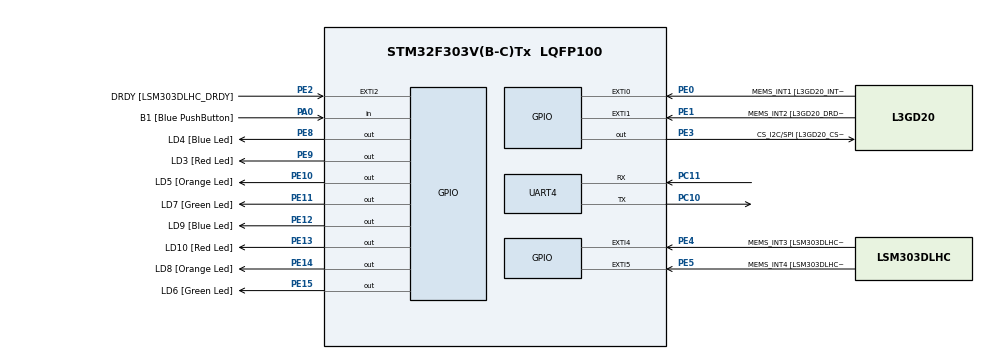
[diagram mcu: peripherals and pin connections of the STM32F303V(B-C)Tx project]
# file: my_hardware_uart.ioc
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Mcu.Family=STM32F3
Mcu.Name=STM32F303V(B-C)Tx
Mcu.Package=LQFP100
NVIC.PriorityGroup=NVIC_PRIORITYGROUP_0
PA0.GPIO_Label=B1 [Blue PushButton]
PA0.GPIO_Mode=GPIO_MODE_INPUT
PA0.GPIO_PuPd=GPIO_NOPULL
PA0.Signal=GPIO_Input
PA11.GPIO_Label=DM
PA11.Signal=USB_DM
PA12.GPIO_Label=DP
PA12.Signal=USB_DP
PA13.GPIO_Label=SWDIO
PA13.Signal=SYS_JTMS-SWDIO
PA14.GPIO_Label=SWCLK
PA14.Signal=SYS_JTCK-SWCLK
PA5.GPIO_Label=SPI1_SCK [L3GD20_SCL/SPC]
PA5.GPIO_Mode=GPIO_MODE_AF_PP
PA5.GPIO_PuPd=GPIO_NOPULL
PA5.GPIO_Speed=GPIO_SPEED_FREQ_LOW
PA5.Signal=SPI1_SCK
PA6.GPIO_Label=SPI1_MISO [L3GD20_SA0/SDO]
PA6.GPIO_Mode=GPIO_MODE_AF_PP
PA6.GPIO_PuPd=GPIO_NOPULL
PA6.GPIO_Speed=GPIO_SPEED_FREQ_LOW
PA6.Signal=SPI1_MISO
PA7.GPIO_Label=SPI1_MISO [L3GD20_SDA/SDI/SDO]
PA7.GPIO_Mode=GPIO_MODE_AF_PP
PA7.GPIO_PuPd=GPIO_NOPULL
PA7.GPIO_Speed=GPIO_SPEED_FREQ_LOW
PA7.Signal=SPI1_MOSI
PB3.GPIO_Label=SWO
PB3.Signal=SYS_JTDO-TRACESWO
PB6.GPIO_FM6=__NULL
PB6.GPIO_Label=I2C1_SCL [LSM303DLHC_SCL]
PB6.GPIO_Mode=GPIO_MODE_AF_OD
PB6.GPIO_PuPd=GPIO_NOPULL
PB6.GPIO_Speed=GPIO_SPEED_FREQ_LOW
PB6.Signal=I2C1_SCL
PB7.GPIO_FM7=__NULL
PB7.GPIO_Label=I2C1_SDA [LSM303DLHC_SDA]
PB7.GPIO_Mode=GPIO_MODE_AF_OD
PB7.GPIO_PuPd=GPIO_NOPULL
PB7.GPIO_Speed=GPIO_SPEED_FREQ_LOW
PB7.Signal=I2C1_SDA
PC10.Mode=Asynchronous
PC10.Signal=UART4_TX
PC11.Mode=Asynchronous
PC11.Signal=UART4_RX
PC14-OSC32_IN.GPIO_Label=OSC32_IN
PC14-OSC32_IN.Signal=RCC_OSC32_IN
PC15-OSC32_OUT.GPIO_Label=OSC32_OUT
PC15-OSC32_OUT.Signal=RCC_OSC32_OUT
PE0.GPIO_Label=MEMS_INT1 [L3GD20_INT1]
PE0.GPIO_ModeDefaultEXTI=GPIO_MODE_EVT_RISING
PE0.GPIO_PuPd=GPIO_NOPULL
PE0.Signal=GPXTI0
PE1.GPIO_Label=MEMS_INT2 [L3GD20_DRDY/INT2]
PE1.GPIO_ModeDefaultEXTI=GPIO_MODE_EVT_RISING
PE1.GPIO_PuPd=GPIO_NOPULL
PE1.Signal=GPXTI1
PE10.GPIO_Label=LD5 [Orange Led]
PE10.GPIO_ModeDefaultOutputPP=GPIO_MODE_OUTPUT_PP
PE10.GPIO_PuPd=GPIO_NOPULL
PE10.GPIO_Speed=GPIO_SPEED_FREQ_LOW
PE10.Signal=GPIO_Output
PE11.GPIO_Label=LD7 [Green Led]
PE11.GPIO_ModeDefaultOutputPP=GPIO_MODE_OUTPUT_PP
PE11.GPIO_PuPd=GPIO_NOPULL
PE11.GPIO_Speed=GPIO_SPEED_FREQ_LOW
PE11.Signal=GPIO_Output
PE12.GPIO_Label=LD9 [Blue Led]
PE12.GPIO_ModeDefaultOutputPP=GPIO_MODE_OUTPUT_PP
PE12.GPIO_PuPd=GPIO_NOPULL
PE12.GPIO_Speed=GPIO_SPEED_FREQ_LOW
PE12.Signal=GPIO_Output
PE13.GPIO_Label=LD10 [Red Led]
PE13.GPIO_ModeDefaultOutputPP=GPIO_MODE_OUTPUT_PP
PE13.GPIO_PuPd=GPIO_NOPULL
PE13.GPIO_Speed=GPIO_SPEED_FREQ_LOW
PE13.Signal=GPIO_Output
PE14.GPIO_Label=LD8 [Orange Led]
PE14.GPIO_ModeDefaultOutputPP=GPIO_MODE_OUTPUT_PP
PE14.GPIO_PuPd=GPIO_NOPULL
PE14.GPIO_Speed=GPIO_SPEED_FREQ_LOW
PE14.Signal=GPIO_Output
PE15.GPIO_Label=LD6 [Green Led]
PE15.GPIO_ModeDefaultOutputPP=GPIO_MODE_OUTPUT_PP
PE15.GPIO_PuPd=GPIO_NOPULL
PE15.GPIO_Speed=GPIO_SPEED_FREQ_LOW
PE15.Signal=GPIO_Output
PE2.GPIO_Label=DRDY [LSM303DLHC_DRDY]
PE2.GPIO_ModeDefaultEXTI=GPIO_MODE_EVT_RISING
PE2.GPIO_PuPd=GPIO_NOPULL
PE2.Signal=GPXTI2
PE3.GPIO_Label=CS_I2C/SPI [L3GD20_CS_I2C/SPI]
PE3.GPIO_ModeDefaultOutputPP=GPIO_MODE_OUTPUT_PP
PE3.GPIO_PuPd=GPIO_NOPULL
PE3.GPIO_Speed=GPIO_SPEED_FREQ_LOW
PE3.Signal=GPIO_Output
PE4.GPIO_Label=MEMS_INT3 [LSM303DLHC_INT1]
PE4.GPIO_ModeDefaultEXTI=GPIO_MODE_EVT_RISING
PE4.GPIO_PuPd=GPIO_NOPULL
PE4.Signal=GPXTI4
PE5.GPIO_Label=MEMS_INT4 [LSM303DLHC_INT2]
PE5.GPIO_ModeDefaultEXTI=GPIO_MODE_EVT_RISING
PE5.GPIO_PuPd=GPIO_NOPULL
PE5.Signal=GPXTI5
PE8.GPIO_Label=LD4 [Blue Led]
PE8.GPIO_ModeDefaultOutputPP=GPIO_MODE_OUTPUT_PP
PE8.GPIO_PuPd=GPIO_NOPULL
PE8.GPIO_Speed=GPIO_SPEED_FREQ_LOW
PE8.Signal=GPIO_Output
PE9.GPIO_Label=LD3 [Red Led]
PE9.GPIO_ModeDefaultOutputPP=GPIO_MODE_OUTPUT_PP
PE9.GPIO_PuPd=GPIO_NOPULL
PE9.GPIO_Speed=GPIO_SPEED_FREQ_LOW
PE9.Signal=GPIO_Output
PF0-OSC_IN.GPIO_Label=OSC_IN
PF0-OSC_IN.Signal=RCC_OSC_IN
PF1-OSC_OUT.GPIO_Label=OSC_OUT
PF1-OSC_OUT.Signal=RCC_OSC_OUT
ProjectManager.HeapSize=0x200
ProjectManager.StackSize=0x400
ProjectManager.TargetToolchain=MDK-ARM V5
RCC.AHBFreq_Value=24000000
RCC.APB1Freq_Value=24000000
RCC.APB1TimFreq_Value=24000000
RCC.APB2Freq_Value=24000000
RCC.APB2TimFreq_Value=24000000
RCC.CortexFreq_Value=24000000
RCC.HCLKFreq_Value=24000000
RCC.HSE_VALUE=8000000
RCC.HSI_VALUE=8000000
RCC.LSE_VALUE=32768
RCC.PLLMUL=RCC_PLL_MUL6
RCC.SYSCLKFreq_VALUE=24000000
RCC.SYSCLKSourceVirtual=RCC_SYSCLKSOURCE_PLLCLK
RCC.USBFreq_Value=24000000
VP_TIM6_VS_ClockSourceINT.Mode=Enable_Timer
VP_TIM7_VS_ClockSourceINT.Mode=Enable_Timer
board=STM32F3DISCOVERY

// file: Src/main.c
/**
  ******************************************************************************
  * @file           : main.c
  * @brief          : Main program body
  ******************************************************************************
  ** This notice applies to any and all portions of this file
  * that are not between comment pairs USER CODE BEGIN and
  * USER CODE END. Other portions of this file, whether
  * inserted by the user or by software development tools
  * are owned by their respective copyright owners.
  *
  * COPYRIGHT(c) 2018 STMicroelectronics
  *
  * Redistribution and use in source and binary forms, with or without modification,
  * are permitted provided that the following conditions are met:
  *   1. Redistributions of source code must retain the above copyright notice,
  *      this list of conditions and the following disclaimer.
  *   2. Redistributions in binary form must reproduce the above copyright notice,
  *      this list of conditions and the following disclaimer in the documentation
  *      and/or other materials provided with the distribution.
  *   3. Neither the name of STMicroelectronics nor the names of its contributors
  *      may be used to endorse or promote products derived from this software
  *      without specific prior written permission.
  *
  * THIS SOFTWARE IS PROVIDED BY THE COPYRIGHT HOLDERS AND CONTRIBUTORS "AS IS"
  * AND ANY EXPRESS OR IMPLIED WARRANTIES, INCLUDING, BUT NOT LIMITED TO, THE
  * IMPLIED WARRANTIES OF MERCHANTABILITY AND FITNESS FOR A PARTICULAR PURPOSE ARE
  * DISCLAIMED. IN NO EVENT SHALL THE COPYRIGHT HOLDER OR CONTRIBUTORS BE LIABLE
  * FOR ANY DIRECT, INDIRECT, INCIDENTAL, SPECIAL, EXEMPLARY, OR CONSEQUENTIAL
  * DAMAGES (INCLUDING, BUT NOT LIMITED TO, PROCUREMENT OF SUBSTITUTE GOODS OR
  * SERVICES; LOSS OF USE, DATA, OR PROFITS; OR BUSINESS INTERRUPTION) HOWEVER
  * CAUSED AND ON ANY THEORY OF LIABILITY, WHETHER IN CONTRACT, STRICT LIABILITY,
  * OR TORT (INCLUDING NEGLIGENCE OR OTHERWISE) ARISING IN ANY WAY OUT OF THE USE
  * OF THIS SOFTWARE, EVEN IF ADVISED OF THE POSSIBILITY OF SUCH DAMAGE.
  *
  ******************************************************************************
  */
#include "main.h"
#include "stm32f3xx_hal.h"
#include "MY_HEADERS.h"
#include <string.h>

TIM_HandleTypeDef htim6;
TIM_HandleTypeDef htim7;

UART_HandleTypeDef huart4;

/* USER CODE BEGIN PV */
/* Private variables ---------------------------------------------------------*/

/* USER CODE END PV */

void SystemClock_Config(void);
static void MX_GPIO_Init(void);
static void MX_UART4_Init(void);
static void MX_TIM6_Init(void);
static void MX_TIM7_Init(void);

/* USER CODE BEGIN PFP */
/* Private function prototypes -----------------------------------------------*/

/* USER CODE END PFP */

/* USER CODE BEGIN 0 */

/* USER CODE BEGIN 4 */
void debugPrint(UART_HandleTypeDef *, char*);

/* USER CODE END 0 */

int main(void)
{

  /* MCU Configuration----------------------------------------------------------*/

  /* Reset of all peripherals, Initializes the Flash interface and the Systick. */
  HAL_Init();

  /* Configure the system clock */
  SystemClock_Config();

  /* Initialize all configured peripherals */
  MX_GPIO_Init();
  MX_TIM6_Init();
  MX_TIM7_Init();
  MX_UART4_Init();
  /* USER CODE BEGIN 2 */
	const uint16_t _size = 1;
	char outbuffer = 0xff;//'H';
	char my_string[_size] = {0};//"I_m_sender_uart4_str_2345678901?"
	uint8_t *my_data;
	uint8_t my_message = 0xFF;
	my_data = &my_message;
	//my_data = (uint8_t*) my_string;
	GPIOE->ODR = 0x00000000;

  /* USER CODE END 2 */

  /* Infinite loop */
  /* USER CODE BEGIN WHILE */
  while (1)
  {
					//debugPrint(&huart4, my_string);
for (;;)
{

	//__HAL_UART_CLEAR_FLAG(huart4, USART_ICR_ORECF);
	if(HAL_TIMEOUT != HAL_UART_Receive(&huart4, my_data, _size, 1000) )//HAL_MAX_DELAY
	{
		if(__HAL_UART_GET_FLAG(&huart4, USART_ICR_ORECF))
		{
			__HAL_UART_CLEAR_FLAG(&huart4, USART_ICR_ORECF);
			GPIOE->ODR = GPIOE->ODR ^ 0x00000200;// PE 9 (RED)
		}
		//my_message = (uint8_t) 'A';
		HAL_UART_Transmit(&huart4, my_data, _size, 1000);

	}
	else
	{
		if(__HAL_UART_GET_FLAG(&huart4, USART_ICR_ORECF))
		{
			__HAL_UART_CLEAR_FLAG(&huart4, USART_ICR_ORECF);
			GPIOE->ODR = GPIOE->ODR ^ 0x00000100;// PE 8
		}
			GPIOE->ODR = GPIOE->ODR ^ 0x00001000;// PE 12
		//my_message = (uint8_t) 'T';
		HAL_UART_Transmit(&huart4, my_data, _size, 1000);

	}

}

  }
  /* USER CODE END 3 */

}

void SystemClock_Config(void)
{

  RCC_OscInitTypeDef RCC_OscInitStruct;
  RCC_ClkInitTypeDef RCC_ClkInitStruct;
  RCC_PeriphCLKInitTypeDef PeriphClkInit;

    /**Initializes the CPU, AHB and APB busses clocks
    */
  RCC_OscInitStruct.OscillatorType = RCC_OSCILLATORTYPE_HSE;
  RCC_OscInitStruct.HSEState = RCC_HSE_ON;
  RCC_OscInitStruct.HSEPredivValue = RCC_HSE_PREDIV_DIV1;
  RCC_OscInitStruct.HSIState = RCC_HSI_ON;
  RCC_OscInitStruct.PLL.PLLState = RCC_PLL_ON;
  RCC_OscInitStruct.PLL.PLLSource = RCC_PLLSOURCE_HSE;
  RCC_OscInitStruct.PLL.PLLMUL = RCC_PLL_MUL9;
  if (HAL_RCC_OscConfig(&RCC_OscInitStruct) != HAL_OK)
  {
    _Error_Handler(__FILE__, __LINE__);
  }

    /**Initializes the CPU, AHB and APB busses clocks
    */
  RCC_ClkInitStruct.ClockType = RCC_CLOCKTYPE_HCLK|RCC_CLOCKTYPE_SYSCLK
                              |RCC_CLOCKTYPE_PCLK1|RCC_CLOCKTYPE_PCLK2;
  RCC_ClkInitStruct.SYSCLKSource = RCC_SYSCLKSOURCE_PLLCLK;
  RCC_ClkInitStruct.AHBCLKDivider = RCC_SYSCLK_DIV1;
  RCC_ClkInitStruct.APB1CLKDivider = RCC_HCLK_DIV2;
  RCC_ClkInitStruct.APB2CLKDivider = RCC_HCLK_DIV1;

  if (HAL_RCC_ClockConfig(&RCC_ClkInitStruct, FLASH_LATENCY_2) != HAL_OK)
  {
    _Error_Handler(__FILE__, __LINE__);
  }

  PeriphClkInit.PeriphClockSelection = RCC_PERIPHCLK_UART4;
  PeriphClkInit.Uart4ClockSelection = RCC_UART4CLKSOURCE_PCLK1;
  if (HAL_RCCEx_PeriphCLKConfig(&PeriphClkInit) != HAL_OK)
  {
    _Error_Handler(__FILE__, __LINE__);
  }

    /**Configure the Systick interrupt time
    */
  HAL_SYSTICK_Config(HAL_RCC_GetHCLKFreq()/1000);

    /**Configure the Systick
    */
  HAL_SYSTICK_CLKSourceConfig(SYSTICK_CLKSOURCE_HCLK);

  /* SysTick_IRQn interrupt configuration */
  HAL_NVIC_SetPriority(SysTick_IRQn, 0, 0);
}

/* TIM6 init function */
static void MX_TIM6_Init(void)
{

  TIM_MasterConfigTypeDef sMasterConfig;

  htim6.Instance = TIM6;
  htim6.Init.Prescaler = 0;
  htim6.Init.CounterMode = TIM_COUNTERMODE_UP;
  htim6.Init.Period = 0;
  htim6.Init.AutoReloadPreload = TIM_AUTORELOAD_PRELOAD_DISABLE;
  if (HAL_TIM_Base_Init(&htim6) != HAL_OK)
  {
    _Error_Handler(__FILE__, __LINE__);
  }

  if (HAL_TIM_OnePulse_Init(&htim6, TIM_OPMODE_SINGLE) != HAL_OK)
  {
    _Error_Handler(__FILE__, __LINE__);
  }

  sMasterConfig.MasterOutputTrigger = TIM_TRGO_RESET;
  sMasterConfig.MasterSlaveMode = TIM_MASTERSLAVEMODE_DISABLE;
  if (HAL_TIMEx_MasterConfigSynchronization(&htim6, &sMasterConfig) != HAL_OK)
  {
    _Error_Handler(__FILE__, __LINE__);
  }

}

/* TIM7 init function */
static void MX_TIM7_Init(void)
{

  TIM_MasterConfigTypeDef sMasterConfig;

  htim7.Instance = TIM7;
  htim7.Init.Prescaler = 0;
  htim7.Init.CounterMode = TIM_COUNTERMODE_UP;
  htim7.Init.Period = 0;
  htim7.Init.AutoReloadPreload = TIM_AUTORELOAD_PRELOAD_DISABLE;
  if (HAL_TIM_Base_Init(&htim7) != HAL_OK)
  {
    _Error_Handler(__FILE__, __LINE__);
  }

  if (HAL_TIM_OnePulse_Init(&htim7, TIM_OPMODE_SINGLE) != HAL_OK)
  {
    _Error_Handler(__FILE__, __LINE__);
  }

  sMasterConfig.MasterOutputTrigger = TIM_TRGO_RESET;
  sMasterConfig.MasterSlaveMode = TIM_MASTERSLAVEMODE_DISABLE;
  if (HAL_TIMEx_MasterConfigSynchronization(&htim7, &sMasterConfig) != HAL_OK)
  {
    _Error_Handler(__FILE__, __LINE__);
  }

}

/* UART4 init function */
static void MX_UART4_Init(void)
{

  huart4.Instance = UART4;
  huart4.Init.BaudRate = 9600;//115200;
  huart4.Init.WordLength = UART_WORDLENGTH_8B;
  huart4.Init.StopBits = UART_STOPBITS_1;
  huart4.Init.Parity = UART_PARITY_NONE;
  huart4.Init.Mode = UART_MODE_TX_RX;
  huart4.Init.HwFlowCtl = UART_HWCONTROL_NONE;
  huart4.Init.OverSampling = UART_OVERSAMPLING_16;
  huart4.Init.OneBitSampling = UART_ONE_BIT_SAMPLE_DISABLE;
  huart4.AdvancedInit.AdvFeatureInit = UART_ADVFEATURE_NO_INIT;
  if (HAL_UART_Init(&huart4) != HAL_OK)
  {
    _Error_Handler(__FILE__, __LINE__);
  }

}

/** Configure pins as
        * Analog
        * Input
        * Output
        * EVENT_OUT
        * EXTI
     PA5   ------> SPI1_SCK
     PA6   ------> SPI1_MISO
     PA7   ------> SPI1_MOSI
     PA11   ------> USB_DM
     PA12   ------> USB_DP
     PB6   ------> I2C1_SCL
     PB7   ------> I2C1_SDA
*/
static void MX_GPIO_Init(void)
{

  GPIO_InitTypeDef GPIO_InitStruct;

  /* GPIO Ports Clock Enable */
  __HAL_RCC_GPIOE_CLK_ENABLE();
  __HAL_RCC_GPIOC_CLK_ENABLE();
  __HAL_RCC_GPIOF_CLK_ENABLE();
  __HAL_RCC_GPIOA_CLK_ENABLE();
  __HAL_RCC_GPIOB_CLK_ENABLE();

  /*Configure GPIO pin Output Level */
  HAL_GPIO_WritePin(GPIOE, CS_I2C_SPI_Pin|LD4_Pin|LD3_Pin|LD5_Pin
                          |LD7_Pin|LD9_Pin|LD10_Pin|LD8_Pin
                          |LD6_Pin, GPIO_PIN_RESET);

  /*Configure GPIO pins : DRDY_Pin MEMS_INT3_Pin MEMS_INT4_Pin MEMS_INT1_Pin
                           MEMS_INT2_Pin */
  GPIO_InitStruct.Pin = DRDY_Pin|MEMS_INT3_Pin|MEMS_INT4_Pin|MEMS_INT1_Pin
                          |MEMS_INT2_Pin;
  GPIO_InitStruct.Mode = GPIO_MODE_EVT_RISING;
  GPIO_InitStruct.Pull = GPIO_NOPULL;
  HAL_GPIO_Init(GPIOE, &GPIO_InitStruct);

  /*Configure GPIO pins : CS_I2C_SPI_Pin LD4_Pin LD3_Pin LD5_Pin
                           LD7_Pin LD9_Pin LD10_Pin LD8_Pin
                           LD6_Pin */
  GPIO_InitStruct.Pin = CS_I2C_SPI_Pin|LD4_Pin|LD3_Pin|LD5_Pin
                          |LD7_Pin|LD9_Pin|LD10_Pin|LD8_Pin
                          |LD6_Pin;
  GPIO_InitStruct.Mode = GPIO_MODE_OUTPUT_PP;
  GPIO_InitStruct.Pull = GPIO_NOPULL;
  GPIO_InitStruct.Speed = GPIO_SPEED_FREQ_LOW;
  HAL_GPIO_Init(GPIOE, &GPIO_InitStruct);

  /*Configure GPIO pin : B1_Pin */
  GPIO_InitStruct.Pin = B1_Pin;
  GPIO_InitStruct.Mode = GPIO_MODE_INPUT;
  GPIO_InitStruct.Pull = GPIO_NOPULL;
  HAL_GPIO_Init(B1_GPIO_Port, &GPIO_InitStruct);

  /*Configure GPIO pins : SPI1_SCK_Pin SPI1_MISO_Pin SPI1_MISOA7_Pin */
  GPIO_InitStruct.Pin = SPI1_SCK_Pin|SPI1_MISO_Pin|SPI1_MISOA7_Pin;
  GPIO_InitStruct.Mode = GPIO_MODE_AF_PP;
  GPIO_InitStruct.Pull = GPIO_NOPULL;
  GPIO_InitStruct.Speed = GPIO_SPEED_FREQ_LOW;
  GPIO_InitStruct.Alternate = GPIO_AF5_SPI1;
  HAL_GPIO_Init(GPIOA, &GPIO_InitStruct);

  /*Configure GPIO pins : DM_Pin DP_Pin */
  GPIO_InitStruct.Pin = DM_Pin|DP_Pin;
  GPIO_InitStruct.Mode = GPIO_MODE_AF_PP;
  GPIO_InitStruct.Pull = GPIO_NOPULL;
  GPIO_InitStruct.Speed = GPIO_SPEED_FREQ_HIGH;
  GPIO_InitStruct.Alternate = GPIO_AF14_USB;
  HAL_GPIO_Init(GPIOA, &GPIO_InitStruct);

  /*Configure GPIO pins : I2C1_SCL_Pin I2C1_SDA_Pin */
  GPIO_InitStruct.Pin = I2C1_SCL_Pin|I2C1_SDA_Pin;
  GPIO_InitStruct.Mode = GPIO_MODE_AF_OD;
  GPIO_InitStruct.Pull = GPIO_PULLUP;
  GPIO_InitStruct.Speed = GPIO_SPEED_FREQ_LOW;
  GPIO_InitStruct.Alternate = GPIO_AF4_I2C1;
  HAL_GPIO_Init(GPIOB, &GPIO_InitStruct);

}

void _Error_Handler(char *file, int line)
{
  while(1)
  {
  }
}

/************************ (C) COPYRIGHT STMicroelectronics *****END OF FILE****/
